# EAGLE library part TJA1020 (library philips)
Lin Transiver Vbat 5...27Volt 3,3Volt support no extra supply needed ->www.lin-subbus.org ->www.semiconductor.philips.com/pip/tja1020t

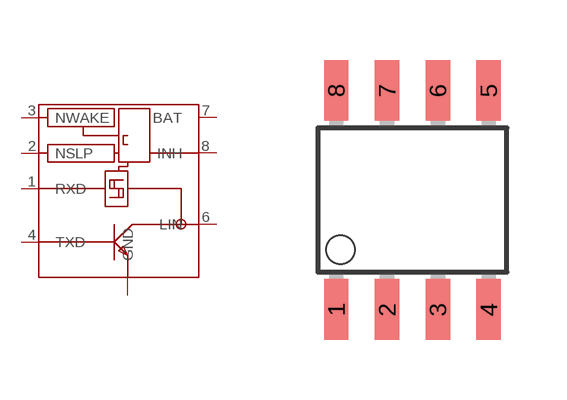
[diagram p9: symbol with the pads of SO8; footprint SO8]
Designator prefix -

## TJA1020SO8  [SO8]
1  RXD  in
2  NSLP  in
3  NWAKE  in
4  TXD  out
5  GND  pwr
6  LIN
7  BAT  pwr
8  INH  out

## Footprint SO8 (pad centres in mm)
smd 0.61 x 1.524: 1 -1.27,-2.743; 2 0,-2.743; 3 1.27,-2.743; 4 2.54,-2.743; 5 2.54,2.743; 6 1.27,2.743; 7 0,2.743; 8 -1.27,2.743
